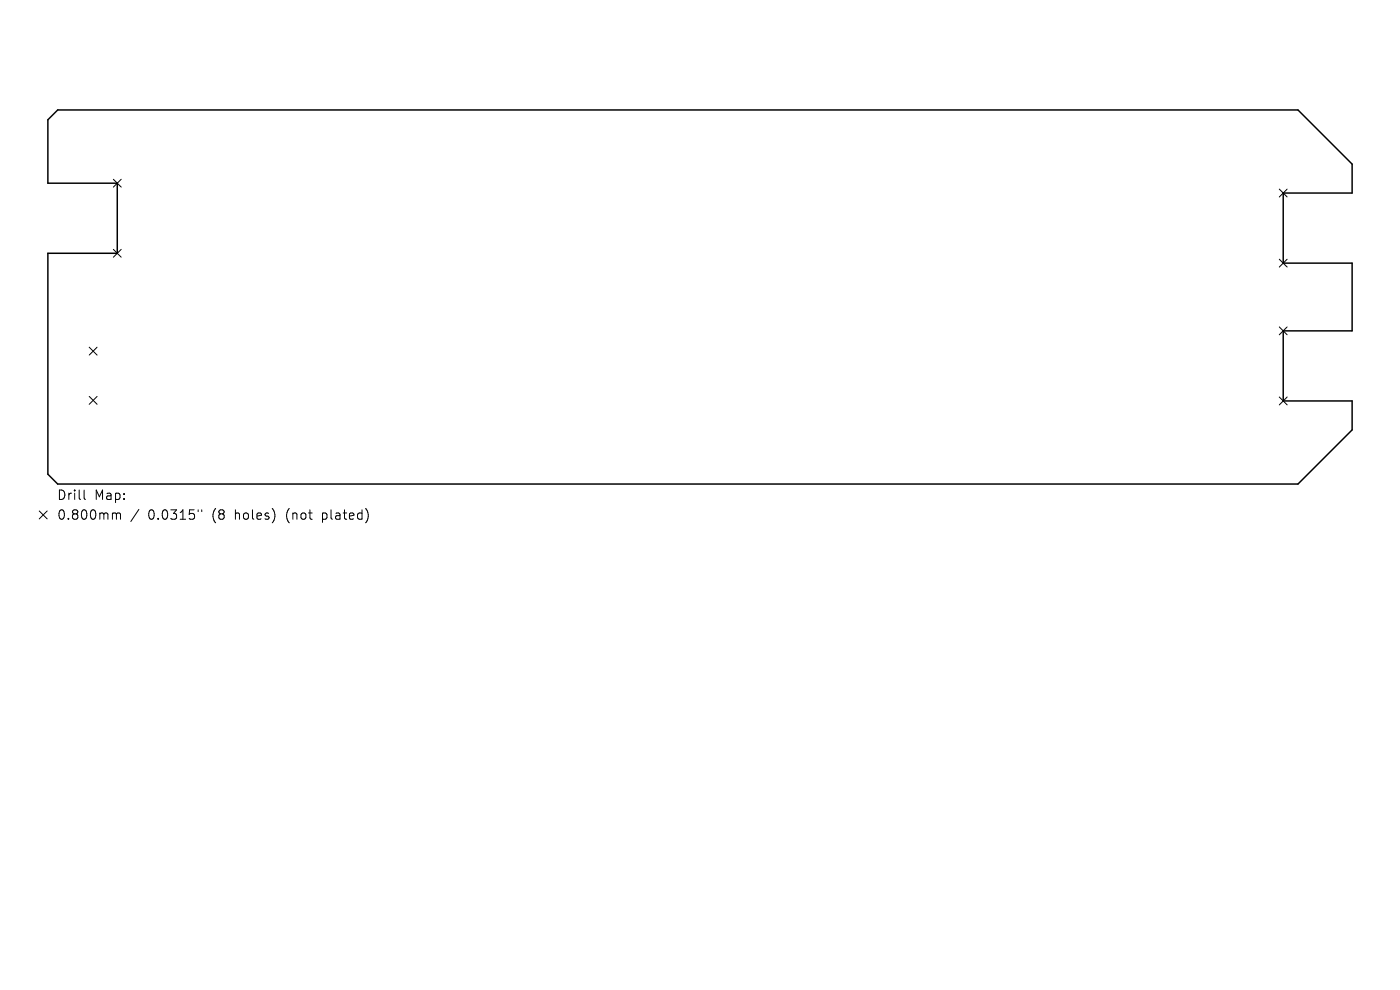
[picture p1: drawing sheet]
<svg xmlns="http://www.w3.org/2000/svg" width="297mm" height="210mm" viewBox="0 0 297 210" stroke-linecap="round" stroke-linejoin="round" font-family="sans-serif">
<defs><g id="words">
<g font-size="2.8">
<text x="12" y="106.3">Drill</text>
<text x="20" y="106.3">Map:</text>
<text x="12" y="110.5">0.800mm</text>
<text x="31.4" y="110.5">0.0315&quot;</text>
<text x="45.2" y="110.5">(8</text>
<text x="50.1" y="110.5">holes)</text>
<text x="61.2" y="110.5">(not</text>
<text x="69" y="110.5">plated)</text>
</g>
</g></defs>
<path d="M10.2 25.4l2-2.1h263.2l11.4 11.5v6.2h-14.6v14.8h14.6v14.4h-14.6v14.9h14.6v6.1l-11.4 11.5h-263.2l-2-2.1v-46.9h14.7v-14.8h-14.7z" fill="none" stroke="#000" stroke-width=".31"/>
<g fill="none" stroke="#000" stroke-width=".21">
<path d="M24 38l1.7 1.7M25.7 38l-1.7 1.7M24 52.9l1.7 1.7M25.7 52.9l-1.7 1.7M271.4 40.1l1.7 1.7M271.4 55l1.7 1.7M273.1 40.1l-1.7 1.7M273.1 55l-1.7 1.7M18.9 73.7l1.7 1.6M20.6 73.7l-1.7 1.6M271.4 69.4l1.7 1.6M273.1 69.4l-1.7 1.6"/>
<path d="M18.9 84.1l1.7 1.7M20.6 84.1l-1.7 1.7M271.4 84.2l1.7 1.7M273.1 84.2l-1.7 1.7M8.3 108.4l1.7 1.7M10 108.4l-1.7 1.7M17.8 103.9v1.8l.3 .2M24.1 108.8h.3l.3 .3M24.7 109.1l.3-.3 .5 .1 .1 1.2M24.7 109.1v1M29.5 108.1l-1.7 2.5M42 108.1v.4"/>
<path d="M42.8 108.1v.4"/>
</g>
<use href="#words"/>
</svg>
